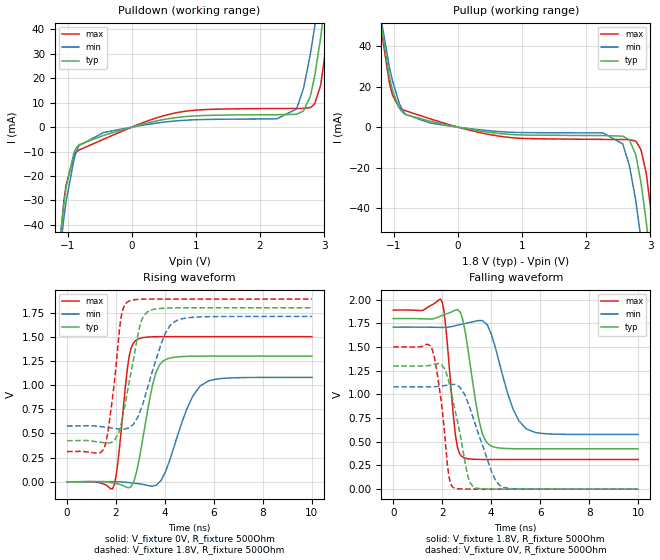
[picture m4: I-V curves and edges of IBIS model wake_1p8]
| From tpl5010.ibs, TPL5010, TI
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|   Model
[Model]   wake_1p8
Model_type   Output
Polarity   Non-Inverting
Vmeas = 0.9
Vref = 0
Cref = 1pF
Rref = 100000
|   typ   min   max
C_comp   0.327pF   0.289pF   0.359pF
[Voltage Range]   1.8   1.71   1.89
[Temperature Range]   25   105   -40
[Pullup Reference]   1.8   1.71   1.89
[Pulldown Reference]   0   0   0
[Power Clamp Reference]   1.8   1.71   1.89
[GND Clamp Reference]   0   0   0
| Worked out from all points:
|   slope of the pulldown table from 0 to 0.27 V, typ, clamps not added: 146 ohm
|   slope of the pullup table from 0 to 0.27 V, typ, clamps not added: 177 ohm
|   falling waveform, V_fixture 1.8V, R_fixture 500Ohm: 20-80 % time 506ps typ, 793ps min, 321ps max; typ from 1.8 V to 0.425 V
|   rising waveform, V_fixture 0V, R_fixture 500Ohm: 20-80 % time 567ps typ, 910ps min, 361ps max; typ from 0 V to 1.3 V
|   rising waveform, V_fixture 1.8V, R_fixture 500Ohm: 20-80 % time 606ps typ, 839ps min, 409ps max; typ from 0.425 V to 1.8 V
|   falling waveform, V_fixture 0V, R_fixture 500Ohm: 20-80 % time 592ps typ, 852ps min, 391ps max; typ from 1.3 V to 0 V
[Pulldown]
|   Voltage   I(typ)   I(min)   I(max)
-1.8V     -271.8mA   -257.9mA   -291.2mA
-1.163V   -57.09mA   -61.48mA   -58.02mA
-1.055V   -30.79mA   -36.57mA   -29.77mA
-822.6mV  -7.198mA   -7.592mA   -9.398mA
689.4mV   3.906mA    2.55mA     5.86mA
2.261V    5.097mA    3.383mA    7.63mA
2.569V    5.26mA     7.409mA    7.662mA
2.795V    13.96mA    31.67mA    8.182mA
2.855V    21.44mA    41.59mA    9.787mA
2.947V    37.02mA    58.6mA     17.52mA
3.087V    66.28mA    87.14mA    43.27mA
3.6V      191.2mA    202.5mA    176.4mA
[Pullup]
|   Voltage   I(typ)   I(min)   I(max)
-1.8V     191.4mA    181.7mA    201.6mA
-1.314V   72.89mA    74.34mA    72.58mA
-1.017V   17.9mA     22.44mA    15.59mA
-817.2mV  6.241mA    6.337mA    8.113mA
689.4mV   -3.276mA   -2.291mA   -4.667mA
2.261V    -4.173mA   -2.877mA   -6.068mA
2.569V    -4.451mA   -8.318mA   -6.133mA
2.763V    -12.99mA   -34.9mA    -6.877mA
2.849V    -26.88mA   -54.53mA   -10.96mA
2.941V    -48.8mA    -78.65mA   -24.49mA
3.033V    -75.26mA   -105mA     -47.89mA
3.6V      -271.4mA   -288mA     -255.1mA
[Ramp]
R_load = 500
|   typ   min   max
dV/dt_r   0.779951/5.67308e-10   0.647827/9.10102e-10   0.900725/3.60774e-10
dV/dt_f   0.82472/5.05871e-10   0.679636/7.93279e-10   0.946234/3.21009e-10
[Falling Waveform]
V_fixture = 1.8V
V_fixture_min = 1.71V
V_fixture_max = 1.89V
R_fixture = 500Ohm
C_fixture = 0F
|   Time   V(typ)   V(min)   V(max)
0s        1.8V       1.71V      1.89V
2.006ns   1.834V     1.706V     1.968V
2.147ns   1.847V     1.707V     1.702V
2.542ns   1.889V     1.725V     562.3mV
2.795ns   1.822V     1.74V      345.6mV
3.491ns   737.1mV    1.779V     314mV
3.916ns   467.5mV    1.688V     313mV
4.889ns   427.1mV    846.4mV    312.9mV
5.438ns   425.7mV    635mV      312.9mV
10ns      425.5mV    577.3mV    312.9mV
[Rising Waveform]
V_fixture = 0V
V_fixture_min = 0V
V_fixture_max = 0V
R_fixture = 500Ohm
C_fixture = 0F
|   Time   V(typ)   V(min)   V(max)
0s        -974nV     -2.083uV   -1.877uV
1.844ns   -10.5mV    1.56mV     -76.34mV
2.073ns   -21.68mV   942.3uV    193.1mV
2.542ns   -58.25mV   -8.57mV    1.305V
2.88ns    151.1mV    -18.34mV   1.474V
3.491ns   1V         -43.94mV   1.499V
3.916ns   1.247V     51.63mV    1.501V
4.889ns   1.297V     750.9mV    1.501V
5.438ns   1.299V     991.9mV    1.501V
10ns      1.3V       1.08V      1.501V
[Rising Waveform]
V_fixture = 1.8V
V_fixture_min = 1.71V
V_fixture_max = 1.89V
R_fixture = 500Ohm
C_fixture = 0F
|   Time   V(typ)   V(min)   V(max)
0s        425.5mV    577.3mV    312.9mV
1.503ns   404.2mV    566.5mV    340.7mV
1.767ns   403.7mV    557.6mV    692.6mV
2.211ns   601.8mV    544.4mV    1.708V
2.468ns   936mV      553.2mV    1.86V
2.958ns   1.598V     710.1mV    1.887V
3.141ns   1.719V     844.9mV    1.889V
3.848ns   1.794V     1.43V      1.89V
4.347ns   1.799V     1.649V     1.89V
10ns      1.8V       1.71V      1.89V
[Falling Waveform]
|Gnd
V_fixture = 0V
V_fixture_min = 0V
V_fixture_max = 0V
R_fixture = 500Ohm
C_fixture = 0F
|   Time   V(typ)   V(min)   V(max)
0s        1.3V       1.08V      1.501V
1.586ns   1.311V     1.08V      1.479V
1.928ns   1.318V     1.087V     982.4mV
2.27ns    1.132V     1.101V     137.8mV
2.468ns   899.9mV    1.105V     14.02mV
2.71ns    603.6mV    1.08V      2.994mV
3.141ns   66.92mV    847.1mV    408.6uV
4.015ns   996.9uV    182.9mV    7.809uV
4.347ns   330.6uV    40.96mV    7.454uV
10ns      2.152uV    -2.201uV   1.415uV
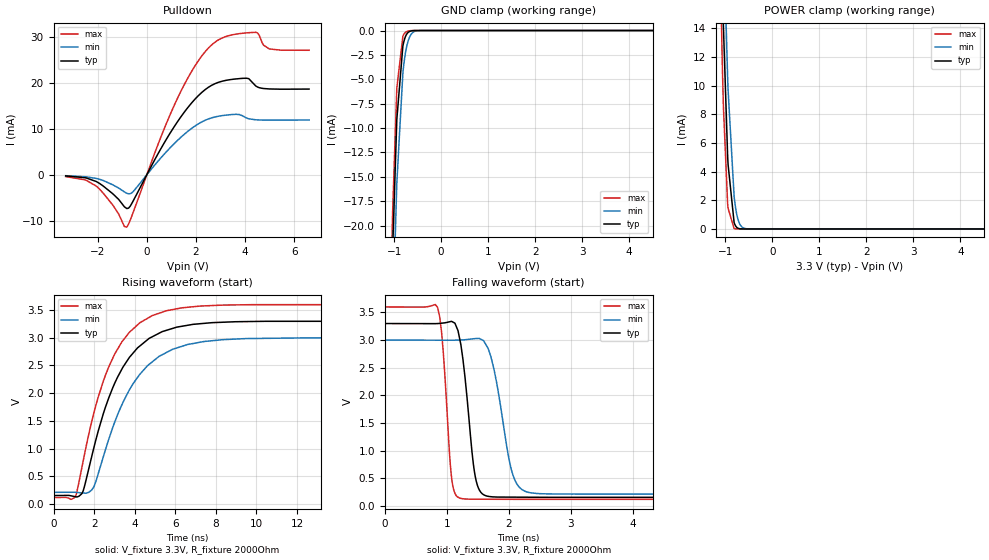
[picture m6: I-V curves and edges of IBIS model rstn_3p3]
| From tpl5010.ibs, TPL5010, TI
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|   Model
[Model]   rstn_3p3
Model_type   I/O_open_drain
Polarity   Non-Inverting
Enable   Active-Low
Vinl = 0.99
Vinh = 2.31
Vmeas = 1.65
Vref = 3.3
Cref = 1pF
Rref = 2000
|   typ   min   max
C_comp   0.474pF   0.343pF   0.582pF
[Voltage Range]   3.3   3   3.6
[Temperature Range]   25   105   -40
[Pullup Reference]   3.3   3   3.6
[Pulldown Reference]   0   0   0
[Power Clamp Reference]   3.3   3   3.6
[GND Clamp Reference]   0   0   0
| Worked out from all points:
|   slope of the pulldown table from 0 to 0.495 V, typ, clamps not added: 100 ohm
|   GND clamp passes 1 mA (typ) near -0.79 V on its own axis
|   POWER clamp passes 1 mA (typ) near -0.83 V on its own axis
|   falling waveform, V_fixture 3.3V, R_fixture 2000Ohm: 20-80 % time 168ps typ, 251ps min, 118ps max; typ from 3.3 V to 0.154 V
|   rising waveform, V_fixture 3.3V, R_fixture 2000Ohm: 20-80 % time 1.96ns typ, 2.12ns min, 1.85ns max; typ from 0.154 V to 3.3 V
[Pulldown]
|   Voltage   I(typ)   I(min)   I(max)
-3.3V     -260.4uA   -210.9uA   -408.3uA
-2.062V   -1.464mA   -801.8uA   -2.457mA
-815.1mV  -7.364mA   -4.037mA   -11.41mA
-567.6mV  -5.826mA   -3.739mA   -8.366mA
1.125V    10.55mA    6.824mA    15.22mA
1.927V    16.26mA    10.48mA    23.42mA
2.61V     19.37mA    12.33mA    28.12mA
3.204V    20.52mA    12.96mA    30.05mA
4.036V    21mA       12.4mA     30.86mA
4.432V    19.31mA    11.95mA    30.99mA
4.976V    18.67mA    11.88mA    27.39mA
6.6V      18.64mA    11.91mA    27.08mA
[GND Clamp]
|   Voltage   I(typ)   I(min)   I(max)
-3.3V     -836.6mA   -780.4mA   -895mA
-1.043V   -24.52mA   -32.26mA   -20.67mA
-1.033V   -22.55mA   -30.3mA    -18.64mA
-943.8mV  -9.134mA   -15.65mA   -5.921mA
-815.1mV  -1.607mA   -4.399mA   -599.1uA
-775.5mV  -830.2uA   -2.781mA   -264.4uA
-726mV    -319.3uA   -1.488mA   -92.99uA
-676.5mV  -109.3uA   -730.3uA   -28.86uA
-627mV    -34.32uA   -315.6uA   -7.627uA
-557.7mV  -5.789uA   -75.32uA   -818.2nA
-458.7mV  -346.3nA   -6.68uA    -11.37nA
6.6V      0A         0A         0A
[POWER Clamp]
|   Voltage   I(typ)   I(min)   I(max)
-3.3V     555.7mA    521.8mA    588.1mA
-1.162V   33.2mA     39.48mA    27.73mA
-1.073V   18.29mA    25.19mA    12.41mA
-1.043V   14.15mA    20.99mA    8.551mA
-953.7mV  5.173mA    10.66mA    1.801mA
-943.8mV  4.511mA    9.75mA     1.446mA
-815.1mV  451.8uA    2.296mA    26.48uA
-765.6mV  135.1uA    1.133mA    3.141uA
-716.1mV  32.23uA    507uA      311.3nA
-646.8mV  3.166uA    134.4uA    4.612nA
-547.8mV  78.06nA    12.71uA    0A
6.6V      0A         0A         0A
[Ramp]
R_load = 2000
|   typ   min   max
dV/dt_r   1.88782/1.96368e-09   1.67305/2.11535e-09   2.08968/1.85017e-09
dV/dt_f   1.88782/1.67507e-10   1.67305/2.51312e-10   2.08968/1.18169e-10
[Falling Waveform]
V_fixture = 3.3V
V_fixture_min = 3V
V_fixture_max = 3.6V
R_fixture = 2000Ohm
C_fixture = 0F
|   Time   V(typ)   V(min)   V(max)
0s        3.3V       3V         3.6V
852.8ps   3.3V       2.999V     3.589V
1.088ns   3.333V     2.998V     420.2mV
1.311ns   2.125V     3.009V     122.4mV
1.429ns   748.5mV    3.025V     119.4mV
1.546ns   247.6mV    3.017V     119mV
1.76ns    160.8mV    2.479V     118.3mV
2.075ns   156.8mV    530.2mV    117.3mV
2.454ns   154.7mV    222.5mV    117.2mV
50ns      153.6mV    211.6mV    117.2mV
[Rising Waveform]
V_fixture = 3.3V
V_fixture_min = 3V
V_fixture_max = 3.6V
R_fixture = 2000Ohm
C_fixture = 0F
|   Time   V(typ)   V(min)   V(max)
0s        153.6mV    211.6mV    117.2mV
1.093ns   130.9mV    211.4mV    148.9mV
1.464ns   242.3mV    199.4mV    783mV
1.922ns   920.4mV    273.7mV    1.549V
2.549ns   1.737V     969.2mV    2.314V
3.415ns   2.467V     1.829V     2.947V
4.237ns   2.847V     2.335V     3.264V
5.561ns   3.134V     2.733V     3.487V
9.476ns   3.292V     2.985V     3.595V
50ns      3.3V       3V         3.6V
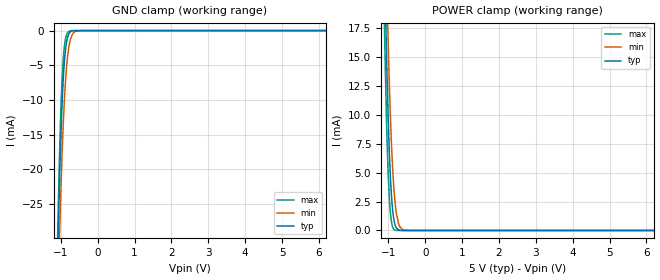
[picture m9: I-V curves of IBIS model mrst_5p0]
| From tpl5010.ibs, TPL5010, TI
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|   Model
[Model]   mrst_5p0
Model_type   Input
Vinl = 1.5
Vinh = 3.5
|   typ   min   max
C_comp   0.404pF   0.345pF   0.463pF
[Voltage Range]   5   4.5   5.5
[Temperature Range]   25   105   -40
[Power Clamp Reference]   5   4.5   5.5
[GND Clamp Reference]   0   0   0
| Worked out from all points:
|   GND clamp passes 1 mA (typ) near -0.82 V on its own axis
|   POWER clamp passes 1 mA (typ) near -0.85 V on its own axis
[GND Clamp]
|   Voltage   I(typ)   I(min)   I(max)
-5V       -1.485A    -1.386A    -1.582A
-1.085V   -32.12mA   -39.94mA   -28.94mA
-1.07V    -28.67mA   -36.65mA   -25.24mA
-1.04V    -22.32mA   -30.44mA   -18.57mA
-1.025V   -19.44mA   -27.54mA   -15.63mA
-995mV    -14.34mA   -22.18mA   -10.62mA
-950mV    -8.403mA   -15.34mA   -5.306mA
-875mV    -2.772mA   -7.296mA   -1.201mA
-770mV    -346uA     -1.938mA   -68.61uA
-665mV    -19.44uA   -344.8uA   -1.131uA
-470mV    -6.622nA   -3.37uA    0A
10V       0A         0A         0A
[POWER Clamp]
|   Voltage   I(typ)   I(min)   I(max)
-5V       994.4mA    930mA      1.055A
-1.115V   24.99mA    31.72mA    19.12mA
-1.1V     22.53mA    29.35mA    16.61mA
-1.07V    17.92mA    24.82mA    12.05mA
-1.01V    10.22mA    16.76mA    5.231mA
-980mV    7.254mA    13.32mA    3.075mA
-905mV    2.505mA    6.675mA    552uA
-860mV    1.136mA    4.046mA    140.6uA
-815mV    450.8uA    2.293mA    26.37uA
-695mV    16.41uA    347.8uA    103nA
-485mV    429.8nA    2.284uA    0A
10V       0A         0A         0A
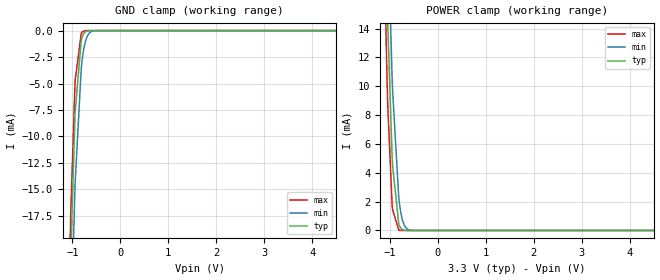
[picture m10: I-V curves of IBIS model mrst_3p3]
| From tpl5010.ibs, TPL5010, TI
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|   Model
[Model]   mrst_3p3
Model_type   Input
Vinl = 0.99
Vinh = 2.31
|   typ   min   max
C_comp   0.404pF   0.345pF   0.463pF
[Voltage Range]   3.3   3   3.6
[Temperature Range]   25   105   -40
[Power Clamp Reference]   3.3   3   3.6
[GND Clamp Reference]   0   0   0
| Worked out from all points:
|   GND clamp passes 1 mA (typ) near -0.82 V on its own axis
|   POWER clamp passes 1 mA (typ) near -0.83 V on its own axis
[GND Clamp]
|   Voltage   I(typ)   I(min)   I(max)
-3.3V     -835mA     -779.1mA   -893.3mA
-1.043V   -22.88mA   -31mA      -19.15mA
-1.033V   -20.93mA   -29.05mA   -17.14mA
-943.8mV  -7.748mA   -14.52mA   -4.767mA
-815.1mV  -922.7uA   -3.573mA   -267.1uA
-795.3mV  -610.7uA   -2.754mA   -151.3uA
-765.6mV  -311.9uA   -1.819mA   -59.36uA
-716.1mV  -87.57uA   -848.3uA   -9.774uA
-666.6mV  -20.45uA   -355.4uA   -1.22uA
-607.2mV  -2.907uA   -105.8uA   -74.25nA
-508.2mV  -76.08nA   -9.474uA   0A
6.6V      0A         0A         0A
[POWER Clamp]
|   Voltage   I(typ)   I(min)   I(max)
-3.3V     555.7mA    521.8mA    588.1mA
-1.162V   33.2mA     39.48mA    27.73mA
-1.073V   18.29mA    25.19mA    12.41mA
-1.043V   14.15mA    20.99mA    8.551mA
-953.7mV  5.173mA    10.66mA    1.801mA
-943.8mV  4.511mA    9.75mA     1.446mA
-815.1mV  451.8uA    2.296mA    26.48uA
-765.6mV  135.1uA    1.133mA    3.139uA
-716.1mV  32.23uA    507uA      309.6nA
-646.8mV  3.165uA    134.4uA    2.845nA
-547.8mV  76.46nA    12.71uA    0A
6.6V      0A         0A         0A
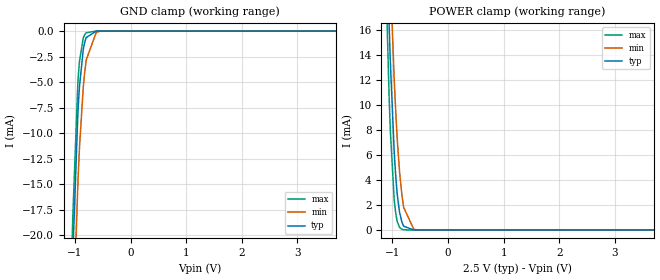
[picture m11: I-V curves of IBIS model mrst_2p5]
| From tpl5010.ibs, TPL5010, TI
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|   Model
[Model]   mrst_2p5
Model_type   Input
Vinl = 0.75
Vinh = 1.75
|   typ   min   max
C_comp   0.404pF   0.345pF   0.463pF
[Voltage Range]   2.5   2.25   2.75
[Temperature Range]   25   105   -40
[Power Clamp Reference]   2.5   2.25   2.75
[GND Clamp Reference]   0   0   0
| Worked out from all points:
|   GND clamp passes 1 mA (typ) near -0.82 V on its own axis
|   POWER clamp passes 1 mA (typ) near -0.85 V on its own axis
[GND Clamp]
|   Voltage   I(typ)   I(min)   I(max)
-2.5V     -530.7mA   -496.8mA   -569mA
-1.045V   -23.33mA   -31.44mA   -19.61mA
-1.038V   -21.83mA   -29.95mA   -18.06mA
-947.5mV  -8.134mA   -15.01mA   -5.083mA
-940mV    -7.365mA   -14.03mA   -4.459mA
-917.5mV  -5.377mA   -11.35mA   -2.934mA
-850mV    -1.796mA   -5.488mA   -665.1uA
-827.5mV  -1.179mA   -4.179mA   -374uA
-797.5mV  -640.2uA   -2.837mA   -161.5uA
-617.5mV  -4.135uA   -132.4uA   -127.3nA
-535mV    -219.8nA   -18.99uA   0A
5V        0A         0A         0A
[POWER Clamp]
|   Voltage   I(typ)   I(min)   I(max)
-2.5V     351.8mA    332.8mA    370.5mA
-1.15V    31.09mA    37.5mA     25.49mA
-1.06V    16.49mA    23.38mA    10.69mA
-1.038V   13.47mA    20.27mA    7.946mA
-962.5mV  5.816mA    11.51mA    2.17mA
-910mV    2.716mA    7.028mA    631.3uA
-872.5mV  1.433mA    4.681mA    212.1uA
-827.5mV  591.6uA    2.703mA    43.27uA
-797.5mV  301.6uA    1.804mA    12.76uA
-617.5mV  1.107uA    70.67uA    0A
-565mV    155.4nA    19.84uA    0A
5V        0A         0A         0A
